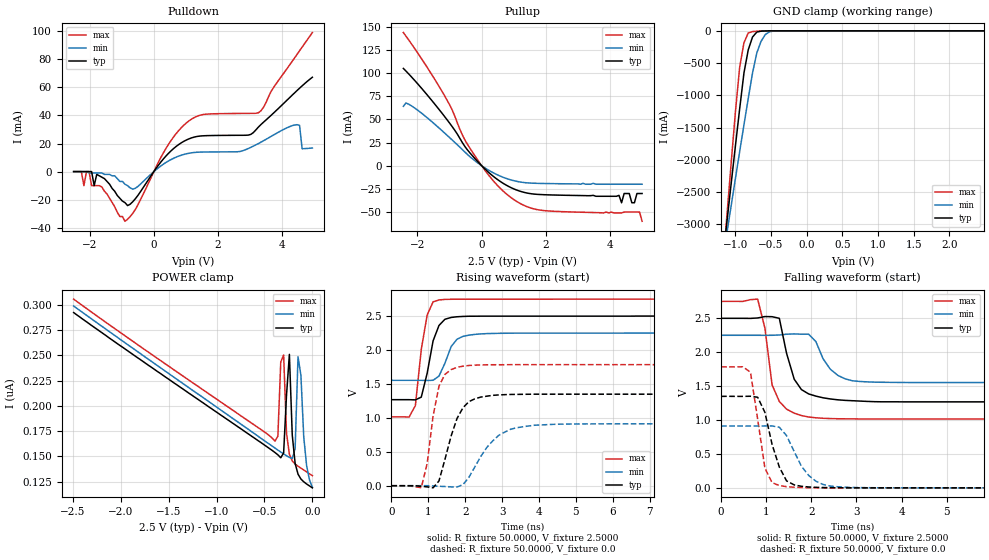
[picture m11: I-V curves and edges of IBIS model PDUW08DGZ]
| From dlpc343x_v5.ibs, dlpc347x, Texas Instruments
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[Model]  PDUW08DGZ
Model_type I/O
Polarity   Non-Inverting
Enable   Active-Low
Vinl =   0.7000V
Vinh =   1.7000V
Vmeas =  1.2500V
Cref =   50.0000pF
Rref =   1.0000M
Vref =   0.0V
C_comp   3.1474pF   3.0371pF   3.2782pF
[Temperature Range]   25.0000   0.1250k   -40.0000
[Voltage Range]   2.5000V   2.2500V   2.7500V
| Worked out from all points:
|   slope of the pulldown table from 0 to 0.375 V, typ, clamps not added: 33.9 ohm
|   slope of the pullup table from 0 to 0.375 V, typ, clamps not added: 31.8 ohm
|   GND clamp passes 1 mA (typ) near -0.53 V on its own axis
|   rising waveform, R_fixture 50.0000, V_fixture 2.5000: 20-80 % time 309ps typ, 353ps min, 249ps max; typ from 1.27 V to 2.5 V
|   rising waveform, R_fixture 50.0000, V_fixture 0.0: 20-80 % time 478ps typ, 722ps min, 299ps max; typ from 0 V to 1.35 V
|   falling waveform, R_fixture 50.0000, V_fixture 2.5000: 20-80 % time 345ps typ, 395ps min, 280ps max; typ from 2.5 V to 1.27 V
|   falling waveform, R_fixture 50.0000, V_fixture 0.0: 20-80 % time 337ps typ, 462ps min, 241ps max; typ from 1.35 V to 0 V
[Pulldown]
|Voltage   I(typ)   I(min)   I(max)
-2.5V     0A         0A         0A
-2.26V    0A         0A         0A
-2.18V    0A         0A         -10mA
-2.02V    0A         -1mA       0A
-1.94V    0A         -1mA       -10mA
-900mV    -22.1mA    -9mA       -35.4mA
860mV     20.57mA    11.71mA    31.37mA
3.26V     31.77mA    20.01mA    41.93mA
4.46V     57.69mA    33.41mA    83.43mA
4.54V     59.39mA    32.94mA    86.05mA
4.62V     61.06mA    16.28mA    88.66mA
4.94V     67.2mA     16.78mA    99.02mA
[Pullup]
|Voltage   I(typ)   I(min)   I(max)
-2.44V    105mA      64.14mA    143.7mA
-1.16V    53.32mA    35.45mA    75.79mA
-360mV    13.64mA    9.556mA    18.59mA
840mV     -22.36mA   -14.58mA   -32.41mA
1.8V      -31.06mA   -19.09mA   -47.82mA
4.28V     -32mA      -20mA      -51mA
4.36V     -40mA      -20mA      -51mA
4.44V     -30mA      -20mA      -50mA
4.6V      -30mA      -20mA      -50mA
4.68V     -40mA      -20mA      -50mA
4.92V     -30mA      -20mA      -50mA
5V        -30mA      -20mA      -60mA
[GND_clamp]
|Voltage   I(typ)   I(min)   I(max)
-2.5V     -17.18A    -13.18A    -22.65A
-1.18V    -3.58A     -3.573A    -3.716A
-1.12V    -2.977A    -3.144A    -2.882A
-1.06V    -2.378A    -2.717A    -2.061A
-940mV    -1.209A    -1.873A    -563mA
-880mV    -653.4mA   -1.458A    -184.6mA
-820mV    -295.6mA   -1.051A    -33.54mA
-760mV    -96.47mA   -655.6mA   -11.44mA
-700mV    -19.54mA   -341.9mA   -6.793mA
-640mV    -4.897mA   -162.3mA   -3.856mA
-520mV    -740.7uA   -14.11mA   -622uA
2.48V     117.6nA    148.7nA    114.2nA
[POWER_clamp]
|Voltage   I(typ)   I(min)   I(max)
-2.49V    292.5nA    299nA      305.8nA
-390mV    153.9nA    158.3nA    165.2nA
-360mV    151.6nA    156.3nA    170.1nA
-330mV    148.7nA    154.4nA    243.5nA
-300mV    153.5nA    152.5nA    250.5nA
-270mV    210.5nA    150.7nA    173.1nA
-240mV    251.1nA    149.1nA    152.2nA
-210mV    171.2nA    148.1nA    145.6nA
-180mV    143.1nA    157.8nA    142.5nA
-150mV    132.5nA    248.6nA    140.4nA
-60mV     122.7nA    140.7nA    134.7nA
0V        118.9nA    119.4nA    131nA
[Ramp]
| variable   typ   min   max
dV/dt_r  0.8094/0.4675n   0.5472/0.7115n   1.0704/0.2993n
dV/dt_f  0.7392/0.3351n   0.4182/0.3892n   1.0410/0.2796n
R_load = 50.0000
[Rising Waveform]
R_fixture= 50.0000
V_fixture= 2.5000
V_fixture_min= 2.2500
V_fixture_max= 2.7500
L_fixture= 0.0H
C_fixture= 0.0F
|time   V(typ)   V(min)   V(max)
0s        1.268V     1.553V     1.015V
480ps     1.268V     1.553V     1.012V
650ps     1.265V     1.553V     1.181V
810ps     1.306V     1.553V     2.01V
970ps     1.659V     1.551V     2.517V
1.13ns    2.135V     1.554V     2.71V
1.29ns    2.362V     1.616V     2.738V
1.78ns    2.49V      2.159V     2.749V
2.42ns    2.499V     2.237V     2.749V
16ns      2.5V       2.25V      2.75V
[Rising Waveform]
R_fixture= 50.0000
V_fixture= 0.0
V_fixture_min= 0.0
V_fixture_max= 0.0
L_fixture= 0.0H
C_fixture= 0.0F
|time   V(typ)   V(min)   V(max)
0s        1.673uV    2.173uV    1.424uV
810ps     -9.143mV   120.5uV    -29.26mV
970ps     -17.26mV   366.7uV    329.7mV
1.13ns    -31.68mV   -3.761mV   1.028V
1.29ns    71.15mV    -8.191mV   1.467V
1.62ns    735.4mV    -17.45mV   1.712V
1.94ns    1.149V     15.32mV    1.762V
2.91ns    1.338V     742.6mV    1.783V
3.88ns    1.349V     891.2mV    1.784V
16ns      1.349V     912mV      1.784V
[Falling Waveform]
R_fixture= 50.0000
V_fixture= 2.5000
V_fixture_min= 2.2500
V_fixture_max= 2.7500
L_fixture= 0.0H
C_fixture= 0.0F
|time   V(typ)   V(min)   V(max)
0s        2.5V       2.25V      2.75V
810ps     2.505V     2.25V      2.783V
970ps     2.526V     2.249V     2.357V
1.13ns    2.524V     2.25V      1.518V
1.29ns    2.5V       2.254V     1.274V
1.62ns    1.602V     2.27V      1.101V
1.94ns    1.385V     2.266V     1.045V
2.42ns    1.311V     1.749V     1.022V
3.07ns    1.28V      1.569V     1.016V
16ns      1.268V     1.553V     1.015V
[Falling Waveform]
R_fixture= 50.0000
V_fixture= 0.0
V_fixture_min= 0.0
V_fixture_max= 0.0
L_fixture= 0.0H
C_fixture= 0.0F
|time   V(typ)   V(min)   V(max)
0s        1.349V     912mV      1.784V
650ps     1.351V     911.9mV    1.706V
810ps     1.336V     911.9mV    1.012V
970ps     1.114V     912.9mV    291.8mV
1.13ns    639.4mV    912.8mV    76.29mV
1.29ns    306.5mV    893.7mV    33.91mV
1.45ns    103.3mV    770.9mV    17.48mV
1.94ns    13.19mV    183.4mV    2.634mV
2.42ns    2.944mV    26.26mV    454.3uV
16ns      0V         0V         0V
